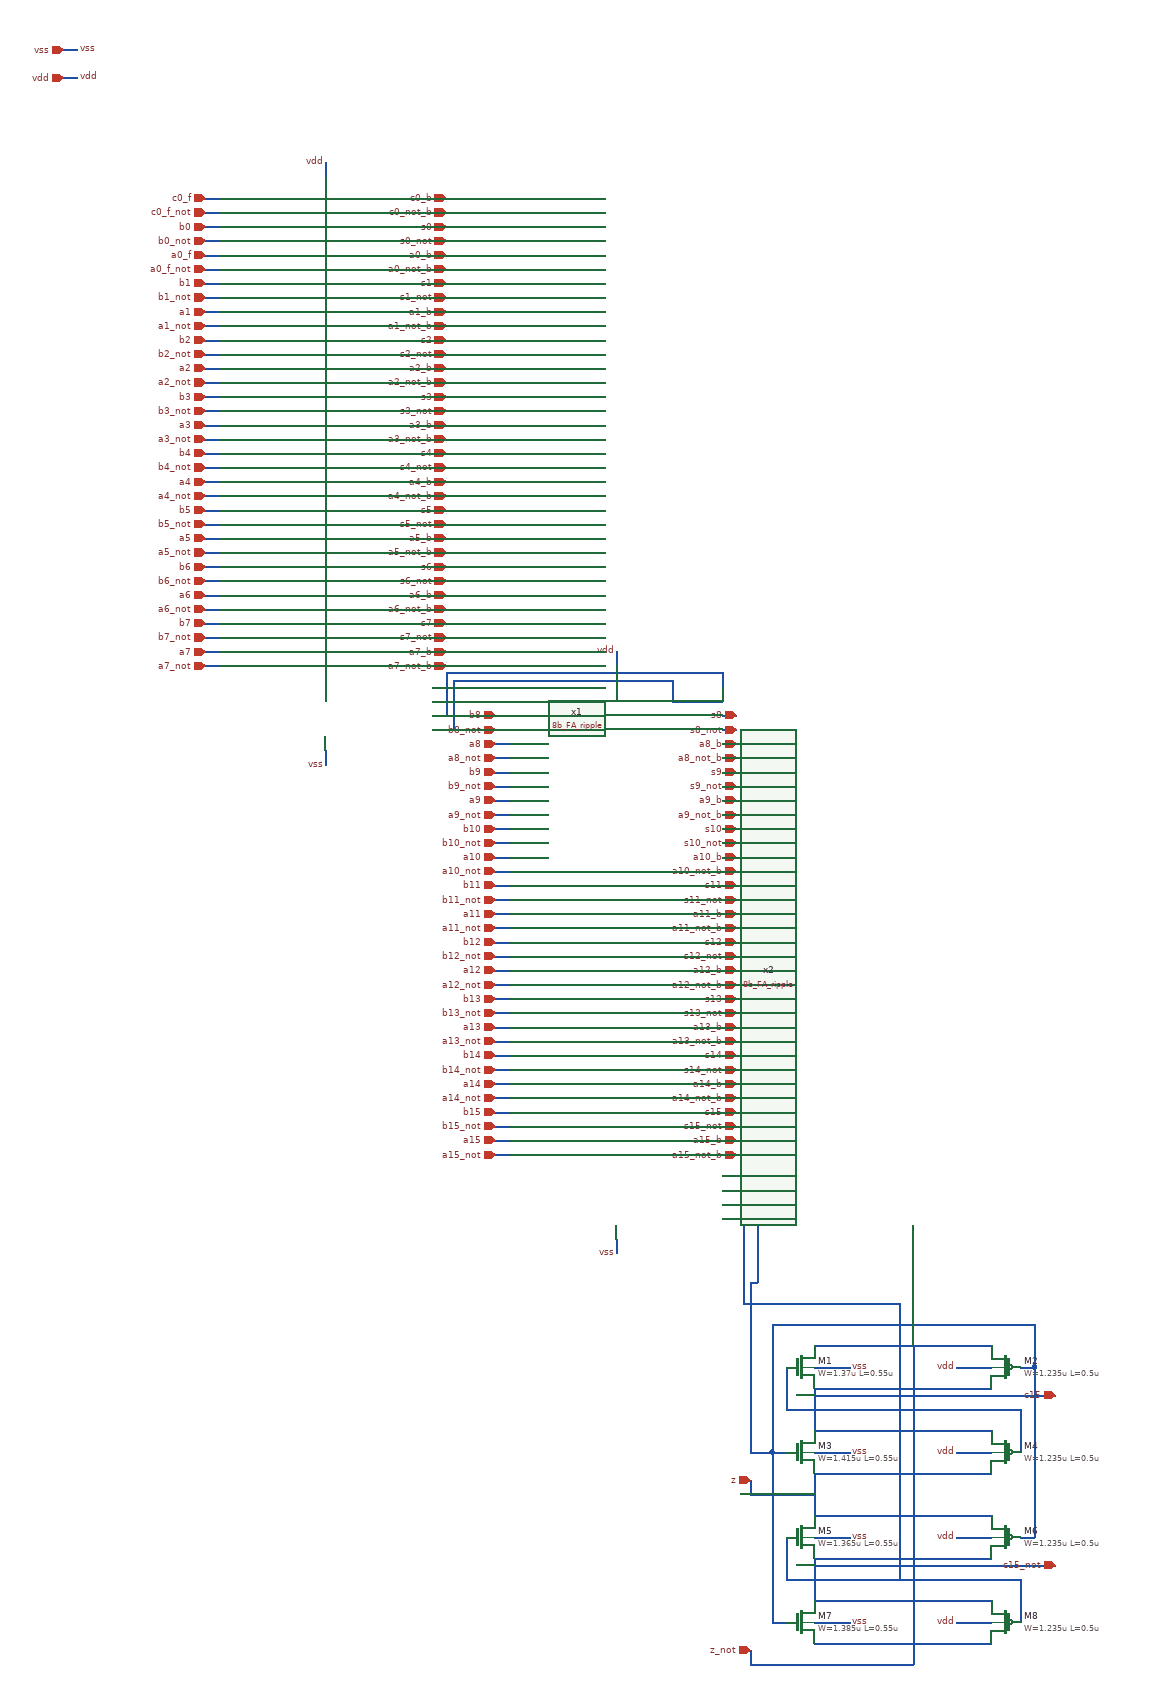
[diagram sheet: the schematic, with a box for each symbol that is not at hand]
v {xschem version=3.4.7 file_version=1.2}
G {}
K {}
V {}
S {}
E {}
N 230 40 340 40 {lab=#net1}
N 230 60 340 60 {lab=#net2}
N 640 770 670 770 {lab=#net3}
N 670 730 670 770 {lab=#net3}
N 640 730 670 730 {lab=#net3}
N 640 750 690 750 {lab=#net4}
N 640 790 690 790 {lab=#net4}
N 690 750 690 790 {lab=#net4}
N 670 770 670 880 {lab=#net3}
N 690 790 690 880 {lab=#net4}
N 230 80 250 80 {lab=#net5}
N 250 30 250 80 {lab=#net5}
N 250 20 250 30 {lab=#net5}
N 250 20 640 20 {lab=#net5}
N 640 20 640 40 {lab=#net5}
N 230 100 260 100 {lab=#net6}
N 260 30 260 100 {lab=#net6}
N 260 30 570 30 {lab=#net6}
N 570 30 570 60 {lab=#net6}
N 570 60 640 60 {lab=#net6}
N 770 970 1020 970 {lab=vss}
N 770 1030 1020 1030 {lab=c15}
N 770 1000 790 1000 {lab=vss}
N 790 1000 820 1000 {lab=vss}
N 970 1000 990 1000 {lab=vdd}
N 990 1000 1020 1000 {lab=vdd}
N 770 1090 1020 1090 {lab=c15}
N 770 1150 1020 1150 {lab=vss}
N 770 1120 790 1120 {lab=vss}
N 790 1120 820 1120 {lab=vss}
N 970 1120 990 1120 {lab=vdd}
N 990 1120 1020 1120 {lab=vdd}
N 770 1030 770 1090 {lab=c15}
N 730 1000 730 1060 {lab=#net3}
N 730 1060 1060 1060 {lab=#net3}
N 1060 1060 1060 1120 {lab=#net3}
N 770 1210 1020 1210 {lab=vss}
N 770 1270 1020 1270 {lab=c15_not}
N 770 1240 790 1240 {lab=vss}
N 790 1240 820 1240 {lab=vss}
N 970 1240 990 1240 {lab=vdd}
N 990 1240 1020 1240 {lab=vdd}
N 770 1330 1020 1330 {lab=c15_not}
N 770 1390 1020 1390 {lab=vss}
N 770 1360 790 1360 {lab=vss}
N 790 1360 820 1360 {lab=vss}
N 970 1360 990 1360 {lab=vdd}
N 990 1360 1020 1360 {lab=vdd}
N 770 1270 770 1330 {lab=c15_not}
N 730 1240 730 1300 {lab=#net3}
N 730 1300 1060 1300 {lab=#net3}
N 1060 1300 1060 1360 {lab=#net3}
N 770 1150 770 1210 {lab=vss}
N 710 1120 730 1120 {lab=#net4}
N 710 910 730 910 {lab=#net3}
N 680 1420 700 1420 {lab=vss}
N 890 910 890 1060 {lab=#net3}
N 890 1060 890 1300 {lab=#net3}
N 680 1120 710 1120 {lab=#net4}
N 1060 1000 1080 1000 {lab=#net4}
N 1080 940 1080 1000 {lab=#net4}
N 1060 1240 1080 1240 {lab=#net4}
N 1080 1000 1080 1240 {lab=#net4}
N 770 1040 1100 1040 {lab=c15}
N 680 1180 770 1180 {lab=vss}
N 670 910 710 910 {lab=#net3}
N 710 1360 730 1360 {lab=#net4}
N 710 940 720 940 {lab=#net4}
N 710 940 710 1120 {lab=#net4}
N 710 1120 710 1360 {lab=#net4}
N 910 970 910 1390 {lab=vss}
N 700 1420 910 1420 {lab=vss}
N 910 1390 910 1420 {lab=vss}
N 1100 1040 1110 1040 {lab=c15}
N 770 1280 1080 1280 {lab=c15_not}
N 1080 1280 1110 1280 {lab=c15_not}
N -290 -860 -270 -860 {lab=vss}
N -290 -820 -270 -820 {lab=vdd}
N 730 910 890 910 {lab=#net3}
N 720 940 1080 940 {lab=#net4}
N 670 880 670 910 {lab=#net3}
N 680 880 680 1120 {lab=#net4}
N 680 880 690 880 {lab=#net4}
N -90 -650 -70 -650 {lab=c0_f}
N -90 -630 -70 -630 {lab=c0_f_not}
N -90 -610 -70 -610 {lab=b0}
N -90 -590 -70 -590 {lab=b0_not}
N -90 -570 -70 -570 {lab=a0_f}
N -90 -550 -70 -550 {lab=a0_f_not}
N -90 -530 -70 -530 {lab=b1}
N -90 -510 -70 -510 {lab=b1_not}
N -90 -490 -70 -490 {lab=a1}
N -90 -470 -70 -470 {lab=a1_not}
N -90 -450 -70 -450 {lab=b2}
N -90 -430 -70 -430 {lab=b2_not}
N -90 -410 -70 -410 {lab=a2}
N -90 -390 -70 -390 {lab=a2_not}
N -90 -370 -70 -370 {lab=b3}
N -90 -350 -70 -350 {lab=b3_not}
N -90 -330 -70 -330 {lab=a3}
N -90 -310 -70 -310 {lab=a3_not}
N -90 -290 -70 -290 {lab=b4}
N -90 -270 -70 -270 {lab=b4_not}
N -90 -250 -70 -250 {lab=a4}
N -90 -230 -70 -230 {lab=a4_not}
N -90 -210 -70 -210 {lab=b5}
N -90 -190 -70 -190 {lab=b5_not}
N -90 -170 -70 -170 {lab=a5}
N -90 -150 -70 -150 {lab=a5_not}
N -90 -130 -70 -130 {lab=b6}
N -90 -110 -70 -110 {lab=b6_not}
N -90 -90 -70 -90 {lab=a6}
N -90 -70 -70 -70 {lab=a6_not}
N -90 -50 -70 -50 {lab=b7}
N -90 -30 -70 -30 {lab=b7_not}
N -90 -10 -70 -10 {lab=a7}
N -90 10 -70 10 {lab=a7_not}
N 230 -650 250 -650 {lab=c0_b}
N 230 -630 250 -630 {lab=c0_not_b}
N 230 -610 250 -610 {lab=s0}
N 230 -590 250 -590 {lab=s0_not}
N 230 -570 250 -570 {lab=a0_b}
N 230 -550 250 -550 {lab=a0_not_b}
N 230 -530 250 -530 {lab=s1}
N 230 -510 250 -510 {lab=s1_not}
N 230 -490 250 -490 {lab=a1_b}
N 230 -470 250 -470 {lab=a1_not_b}
N 230 -450 250 -450 {lab=s2}
N 230 -430 250 -430 {lab=s2_not}
N 230 -410 250 -410 {lab=a2_not}
N 230 -390 250 -390 {lab=a2_not_b}
N 230 -370 250 -370 {lab=s3}
N 230 -350 250 -350 {lab=s3_not}
N 230 -330 250 -330 {lab=a3_b}
N 230 -310 250 -310 {lab=a3_not_b}
N 230 -290 250 -290 {lab=s4}
N 230 -270 250 -270 {lab=s4_not}
N 230 -250 250 -250 {lab=a4_b}
N 230 -230 250 -230 {lab=a4_not_b}
N 230 -210 250 -210 {lab=s5}
N 230 -190 250 -190 {lab=s5_not}
N 230 -170 250 -170 {lab=a5_b}
N 230 -150 250 -150 {lab=a5_not_b}
N 230 -130 250 -130 {lab=s6}
N 230 -110 250 -110 {lab=s6_not}
N 230 -90 250 -90 {lab=a6_b}
N 230 -70 250 -70 {lab=a6_not_b}
N 230 -50 250 -50 {lab=s7}
N 230 -30 250 -30 {lab=s7_not}
N 230 -10 250 -10 {lab=a7_b}
N 230 10 250 10 {lab=a7_not_b}
N 320 80 340 80 {lab=b8}
N 320 100 340 100 {lab=b8_not}
N 320 120 340 120 {lab=a8}
N 320 140 340 140 {lab=a8_not}
N 320 160 340 160 {lab=b9}
N 320 180 340 180 {lab=b9_not}
N 320 200 340 200 {lab=a9}
N 320 220 340 220 {lab=a9_not}
N 320 240 340 240 {lab=b10}
N 320 260 340 260 {lab=b10_not}
N 320 280 340 280 {lab=a10}
N 320 300 340 300 {lab=a10_not}
N 320 320 340 320 {lab=b11}
N 320 340 340 340 {lab=b11_not}
N 320 360 340 360 {lab=a11}
N 320 380 340 380 {lab=a11_not}
N 320 400 340 400 {lab=b12}
N 320 420 340 420 {lab=b12_not}
N 320 440 340 440 {lab=a12}
N 320 460 340 460 {lab=a12_not}
N 320 480 340 480 {lab=b13}
N 320 500 340 500 {lab=b13_not}
N 320 520 340 520 {lab=a13}
N 320 540 340 540 {lab=a13_not}
N 320 560 340 560 {lab=b14}
N 320 580 340 580 {lab=b14_not}
N 320 600 340 600 {lab=a14}
N 320 620 340 620 {lab=a14_not}
N 320 640 340 640 {lab=b15}
N 320 660 340 660 {lab=b15_not}
N 320 680 340 680 {lab=a15}
N 320 700 340 700 {lab=a15_not}
N 640 700 660 700 {lab=a15_not_b}
N 640 680 660 680 {lab=a15_b}
N 640 660 660 660 {lab=s15_not}
N 640 640 660 640 {lab=s15}
N 640 620 660 620 {lab=a14_not_b}
N 640 600 660 600 {lab=a14_b}
N 640 580 660 580 {lab=s14_not}
N 640 560 660 560 {lab=s14}
N 640 540 660 540 {lab=a13_not_b}
N 640 520 660 520 {lab=a13_b}
N 640 500 660 500 {lab=s13_not}
N 640 480 660 480 {lab=s13}
N 640 460 660 460 {lab=a12_not_b}
N 640 440 660 440 {lab=a12_b}
N 640 420 660 420 {lab=s12_not}
N 640 400 660 400 {lab=s12}
N 640 380 660 380 {lab=a11_not_b}
N 640 360 660 360 {lab=a11_b}
N 640 340 660 340 {lab=s11_not}
N 640 320 660 320 {lab=s11}
N 640 300 660 300 {lab=a10_not_b}
N 640 80 660 80 {lab=s8}
N 640 100 660 100 {lab=s8_not}
N 640 120 660 120 {lab=a8_b}
N 640 140 660 140 {lab=a8_not_b}
N 640 160 660 160 {lab=s9}
N 640 180 660 180 {lab=s9_not}
N 640 200 660 200 {lab=a9_b}
N 640 220 660 220 {lab=a9_not_b}
N 640 240 660 240 {lab=s10}
N 640 260 660 260 {lab=s10_not}
N 640 280 660 280 {lab=a10_b}
N 490 820 490 840 {lab=vss}
N 80 130 80 150 {lab=vss}
N 80 -700 80 -680 {lab=vdd}
N 490 -10 490 10 {lab=vdd}
N 680 1160 680 1180 {lab=vss}
N 680 1400 680 1420 {lab=vss}
C {symbols/nfet_03v3.sym} 750 1000 0 0 {name=M1
L=0.55u
W=1.37u
nf=1
m=1
ad="'int((nf+1)/2) * W/nf * 0.18u'"
pd="'2*int((nf+1)/2) * (W/nf + 0.18u)'"
as="'int((nf+2)/2) * W/nf * 0.18u'"
ps="'2*int((nf+2)/2) * (W/nf + 0.18u)'"
nrd="'0.18u / W'" nrs="'0.18u / W'"
sa=0 sb=0 sd=0
model=nfet_03v3
spiceprefix=X
}
C {symbols/pfet_03v3.sym} 1040 1000 2 0 {name=M2
L=0.5u
W=1.235u
nf=1
m=1
ad="'int((nf+1)/2) * W/nf * 0.18u'"
pd="'2*int((nf+1)/2) * (W/nf + 0.18u)'"
as="'int((nf+2)/2) * W/nf * 0.18u'"
ps="'2*int((nf+2)/2) * (W/nf + 0.18u)'"
nrd="'0.18u / W'" nrs="'0.18u / W'"
sa=0 sb=0 sd=0
model=pfet_03v3
spiceprefix=X
}
C {lab_wire.sym} 820 1000 2 0 {name=p2 sig_type=std_logic lab=vss}
C {lab_wire.sym} 970 1000 0 0 {name=p3 sig_type=std_logic lab=vdd}
C {symbols/nfet_03v3.sym} 750 1120 0 0 {name=M3
L=0.55u
W=1.415u
nf=1
m=1
ad="'int((nf+1)/2) * W/nf * 0.18u'"
pd="'2*int((nf+1)/2) * (W/nf + 0.18u)'"
as="'int((nf+2)/2) * W/nf * 0.18u'"
ps="'2*int((nf+2)/2) * (W/nf + 0.18u)'"
nrd="'0.18u / W'" nrs="'0.18u / W'"
sa=0 sb=0 sd=0
model=nfet_03v3
spiceprefix=X
}
C {symbols/pfet_03v3.sym} 1040 1120 2 0 {name=M4
L=0.5u
W=1.235u
nf=1
m=1
ad="'int((nf+1)/2) * W/nf * 0.18u'"
pd="'2*int((nf+1)/2) * (W/nf + 0.18u)'"
as="'int((nf+2)/2) * W/nf * 0.18u'"
ps="'2*int((nf+2)/2) * (W/nf + 0.18u)'"
nrd="'0.18u / W'" nrs="'0.18u / W'"
sa=0 sb=0 sd=0
model=pfet_03v3
spiceprefix=X
}
C {lab_wire.sym} 820 1120 2 0 {name=p4 sig_type=std_logic lab=vss}
C {lab_wire.sym} 970 1120 0 0 {name=p5 sig_type=std_logic lab=vdd}
C {symbols/nfet_03v3.sym} 750 1240 0 0 {name=M5
L=0.55u
W=1.365u
nf=1
m=1
ad="'int((nf+1)/2) * W/nf * 0.18u'"
pd="'2*int((nf+1)/2) * (W/nf + 0.18u)'"
as="'int((nf+2)/2) * W/nf * 0.18u'"
ps="'2*int((nf+2)/2) * (W/nf + 0.18u)'"
nrd="'0.18u / W'" nrs="'0.18u / W'"
sa=0 sb=0 sd=0
model=nfet_03v3
spiceprefix=X
}
C {symbols/pfet_03v3.sym} 1040 1240 2 0 {name=M6
L=0.5u
W=1.235u
nf=1
m=1
ad="'int((nf+1)/2) * W/nf * 0.18u'"
pd="'2*int((nf+1)/2) * (W/nf + 0.18u)'"
as="'int((nf+2)/2) * W/nf * 0.18u'"
ps="'2*int((nf+2)/2) * (W/nf + 0.18u)'"
nrd="'0.18u / W'" nrs="'0.18u / W'"
sa=0 sb=0 sd=0
model=pfet_03v3
spiceprefix=X
}
C {lab_wire.sym} 820 1240 2 0 {name=p6 sig_type=std_logic lab=vss}
C {lab_wire.sym} 970 1240 0 0 {name=p7 sig_type=std_logic lab=vdd}
C {symbols/nfet_03v3.sym} 750 1360 0 0 {name=M7
L=0.55u
W=1.385u
nf=1
m=1
ad="'int((nf+1)/2) * W/nf * 0.18u'"
pd="'2*int((nf+1)/2) * (W/nf + 0.18u)'"
as="'int((nf+2)/2) * W/nf * 0.18u'"
ps="'2*int((nf+2)/2) * (W/nf + 0.18u)'"
nrd="'0.18u / W'" nrs="'0.18u / W'"
sa=0 sb=0 sd=0
model=nfet_03v3
spiceprefix=X
}
C {symbols/pfet_03v3.sym} 1040 1360 2 0 {name=M8
L=0.5u
W=1.235u
nf=1
m=1
ad="'int((nf+1)/2) * W/nf * 0.18u'"
pd="'2*int((nf+1)/2) * (W/nf + 0.18u)'"
as="'int((nf+2)/2) * W/nf * 0.18u'"
ps="'2*int((nf+2)/2) * (W/nf + 0.18u)'"
nrd="'0.18u / W'" nrs="'0.18u / W'"
sa=0 sb=0 sd=0
model=pfet_03v3
spiceprefix=X
}
C {lab_wire.sym} 820 1360 2 0 {name=p8 sig_type=std_logic lab=vss}
C {lab_wire.sym} 970 1360 0 0 {name=p9 sig_type=std_logic lab=vdd}
C {iopin.sym} -290 -860 2 0 {name=p13 lab=vss}
C {iopin.sym} -290 -820 2 0 {name=p14 lab=vdd}
C {iopin.sym} 1110 1040 0 0 {name=p15 lab=c15}
C {iopin.sym} 1110 1280 0 0 {name=p18 lab=c15_not}
C {lab_wire.sym} -270 -860 2 0 {name=p19 sig_type=std_logic lab=vss}
C {lab_wire.sym} -270 -820 2 0 {name=p20 sig_type=std_logic lab=vdd}
C {iopin.sym} -90 -630 2 0 {name=p11 lab=c0_f_not}
C {iopin.sym} -90 -570 2 0 {name=p12 lab=a0_f}
C {iopin.sym} -90 -650 2 0 {name=p16 lab=c0_f}
C {iopin.sym} -90 -610 2 0 {name=p17 lab=b0}
C {iopin.sym} -90 -550 2 0 {name=p21 lab=a0_f_not}
C {iopin.sym} -90 -510 2 0 {name=p22 lab=b1_not}
C {iopin.sym} -90 -590 2 0 {name=p23 lab=b0_not}
C {iopin.sym} -90 -530 2 0 {name=p24 lab=b1}
C {iopin.sym} -90 -470 2 0 {name=p25 lab=a1_not}
C {iopin.sym} -90 -430 2 0 {name=p26 lab=b2_not}
C {iopin.sym} -90 -490 2 0 {name=p27 lab=a1}
C {iopin.sym} -90 -450 2 0 {name=p28 lab=b2}
C {iopin.sym} -90 -390 2 0 {name=p29 lab=a2_not}
C {iopin.sym} -90 -350 2 0 {name=p30 lab=b3_not}
C {iopin.sym} -90 -410 2 0 {name=p31 lab=a2}
C {iopin.sym} -90 -370 2 0 {name=p32 lab=b3}
C {iopin.sym} -90 -310 2 0 {name=p33 lab=a3_not}
C {iopin.sym} -90 -270 2 0 {name=p34 lab=b4_not}
C {iopin.sym} -90 -330 2 0 {name=p35 lab=a3}
C {iopin.sym} -90 -290 2 0 {name=p36 lab=b4}
C {iopin.sym} -90 -230 2 0 {name=p37 lab=a4_not}
C {iopin.sym} -90 -190 2 0 {name=p38 lab=b5_not}
C {iopin.sym} -90 -250 2 0 {name=p39 lab=a4}
C {iopin.sym} -90 -210 2 0 {name=p40 lab=b5}
C {iopin.sym} -90 -150 2 0 {name=p41 lab=a5_not}
C {iopin.sym} -90 -110 2 0 {name=p42 lab=b6_not}
C {iopin.sym} -90 -170 2 0 {name=p43 lab=a5}
C {iopin.sym} -90 -130 2 0 {name=p44 lab=b6}
C {iopin.sym} -90 -70 2 0 {name=p45 lab=a6_not}
C {iopin.sym} -90 -30 2 0 {name=p46 lab=b7_not}
C {iopin.sym} -90 -90 2 0 {name=p47 lab=a6}
C {iopin.sym} -90 -50 2 0 {name=p48 lab=b7}
C {iopin.sym} -90 10 2 0 {name=p49 lab=a7_not}
C {iopin.sym} -90 -10 2 0 {name=p50 lab=a7}
C {iopin.sym} 250 -10 0 0 {name=p51 lab=a7_b}
C {iopin.sym} 250 -50 0 0 {name=p52 lab=s7}
C {iopin.sym} 250 10 0 0 {name=p53 lab=a7_not_b}
C {iopin.sym} 250 -30 0 0 {name=p54 lab=s7_not}
C {iopin.sym} 250 -90 0 0 {name=p55 lab=a6_b}
C {iopin.sym} 250 -130 0 0 {name=p56 lab=s6}
C {iopin.sym} 250 -70 0 0 {name=p57 lab=a6_not_b}
C {iopin.sym} 250 -110 0 0 {name=p58 lab=s6_not}
C {iopin.sym} 250 -170 0 0 {name=p59 lab=a5_b}
C {iopin.sym} 250 -210 0 0 {name=p60 lab=s5}
C {iopin.sym} 250 -150 0 0 {name=p61 lab=a5_not_b}
C {iopin.sym} 250 -190 0 0 {name=p62 lab=s5_not}
C {iopin.sym} 250 -250 0 0 {name=p63 lab=a4_b}
C {iopin.sym} 250 -290 0 0 {name=p64 lab=s4}
C {iopin.sym} 250 -230 0 0 {name=p65 lab=a4_not_b}
C {iopin.sym} 250 -270 0 0 {name=p66 lab=s4_not}
C {iopin.sym} 250 -330 0 0 {name=p67 lab=a3_b}
C {iopin.sym} 250 -370 0 0 {name=p68 lab=s3}
C {iopin.sym} 250 -310 0 0 {name=p69 lab=a3_not_b}
C {iopin.sym} 250 -350 0 0 {name=p70 lab=s3_not}
C {iopin.sym} 250 -410 0 0 {name=p71 lab=a2_b}
C {iopin.sym} 250 -450 0 0 {name=p72 lab=s2}
C {iopin.sym} 250 -390 0 0 {name=p73 lab=a2_not_b}
C {iopin.sym} 250 -430 0 0 {name=p74 lab=s2_not}
C {iopin.sym} 250 -490 0 0 {name=p75 lab=a1_b}
C {iopin.sym} 250 -530 0 0 {name=p76 lab=s1}
C {iopin.sym} 250 -470 0 0 {name=p77 lab=a1_not_b}
C {iopin.sym} 250 -510 0 0 {name=p78 lab=s1_not}
C {iopin.sym} 250 -570 0 0 {name=p79 lab=a0_b}
C {iopin.sym} 250 -610 0 0 {name=p80 lab=s0}
C {iopin.sym} 250 -550 0 0 {name=p81 lab=a0_not_b}
C {iopin.sym} 250 -590 0 0 {name=p82 lab=s0_not}
C {iopin.sym} 250 -650 0 0 {name=p83 lab=c0_b}
C {iopin.sym} 250 -630 0 0 {name=p84 lab=c0_not_b}
C {iopin.sym} 320 100 2 0 {name=p85 lab=b8_not}
C {iopin.sym} 320 140 2 0 {name=p86 lab=a8_not}
C {iopin.sym} 320 80 2 0 {name=p87 lab=b8}
C {iopin.sym} 320 120 2 0 {name=p88 lab=a8}
C {iopin.sym} 320 180 2 0 {name=p89 lab=b9_not}
C {iopin.sym} 320 220 2 0 {name=p90 lab=a9_not}
C {iopin.sym} 320 160 2 0 {name=p91 lab=b9}
C {iopin.sym} 320 200 2 0 {name=p92 lab=a9}
C {iopin.sym} 320 260 2 0 {name=p93 lab=b10_not}
C {iopin.sym} 320 300 2 0 {name=p94 lab=a10_not}
C {iopin.sym} 320 240 2 0 {name=p95 lab=b10}
C {iopin.sym} 320 280 2 0 {name=p96 lab=a10}
C {iopin.sym} 320 340 2 0 {name=p97 lab=b11_not}
C {iopin.sym} 320 380 2 0 {name=p98 lab=a11_not}
C {iopin.sym} 320 320 2 0 {name=p99 lab=b11}
C {iopin.sym} 320 360 2 0 {name=p100 lab=a11}
C {iopin.sym} 320 420 2 0 {name=p101 lab=b12_not}
C {iopin.sym} 320 460 2 0 {name=p102 lab=a12_not}
C {iopin.sym} 320 400 2 0 {name=p103 lab=b12}
C {iopin.sym} 320 440 2 0 {name=p104 lab=a12}
C {iopin.sym} 320 500 2 0 {name=p105 lab=b13_not}
C {iopin.sym} 320 540 2 0 {name=p106 lab=a13_not}
C {iopin.sym} 320 480 2 0 {name=p107 lab=b13}
C {iopin.sym} 320 520 2 0 {name=p108 lab=a13}
C {iopin.sym} 320 580 2 0 {name=p109 lab=b14_not}
C {iopin.sym} 320 620 2 0 {name=p110 lab=a14_not}
C {iopin.sym} 320 560 2 0 {name=p111 lab=b14}
C {iopin.sym} 320 600 2 0 {name=p112 lab=a14}
C {iopin.sym} 320 660 2 0 {name=p113 lab=b15_not}
C {iopin.sym} 320 700 2 0 {name=p114 lab=a15_not}
C {iopin.sym} 320 640 2 0 {name=p115 lab=b15}
C {iopin.sym} 320 680 2 0 {name=p116 lab=a15}
C {iopin.sym} 660 680 0 0 {name=p117 lab=a15_b}
C {iopin.sym} 660 640 0 0 {name=p118 lab=s15}
C {iopin.sym} 660 660 0 0 {name=p119 lab=s15_not}
C {iopin.sym} 660 600 0 0 {name=p120 lab=a14_b}
C {iopin.sym} 660 560 0 0 {name=p121 lab=s14}
C {iopin.sym} 660 620 0 0 {name=p122 lab=a14_not_b}
C {iopin.sym} 660 580 0 0 {name=p123 lab=s14_not}
C {iopin.sym} 660 520 0 0 {name=p124 lab=a13_b}
C {iopin.sym} 660 480 0 0 {name=p125 lab=s13}
C {iopin.sym} 660 540 0 0 {name=p126 lab=a13_not_b}
C {iopin.sym} 660 500 0 0 {name=p127 lab=s13_not}
C {iopin.sym} 660 440 0 0 {name=p128 lab=a12_b}
C {iopin.sym} 660 400 0 0 {name=p129 lab=s12}
C {iopin.sym} 660 460 0 0 {name=p130 lab=a12_not_b}
C {iopin.sym} 660 420 0 0 {name=p131 lab=s12_not}
C {iopin.sym} 660 360 0 0 {name=p132 lab=a11_b}
C {iopin.sym} 660 320 0 0 {name=p133 lab=s11}
C {iopin.sym} 660 380 0 0 {name=p134 lab=a11_not_b}
C {iopin.sym} 660 340 0 0 {name=p135 lab=s11_not}
C {iopin.sym} 660 280 0 0 {name=p136 lab=a10_b}
C {iopin.sym} 660 240 0 0 {name=p137 lab=s10}
C {iopin.sym} 660 300 0 0 {name=p138 lab=a10_not_b}
C {iopin.sym} 660 260 0 0 {name=p139 lab=s10_not}
C {iopin.sym} 660 200 0 0 {name=p140 lab=a9_b}
C {iopin.sym} 660 160 0 0 {name=p141 lab=s9}
C {iopin.sym} 660 220 0 0 {name=p142 lab=a9_not_b}
C {iopin.sym} 660 180 0 0 {name=p143 lab=s9_not}
C {iopin.sym} 660 120 0 0 {name=p144 lab=a8_b}
C {iopin.sym} 660 80 0 0 {name=p145 lab=s8}
C {iopin.sym} 660 140 0 0 {name=p146 lab=a8_not_b}
C {iopin.sym} 660 100 0 0 {name=p147 lab=s8_not}
C {iopin.sym} 660 700 0 0 {name=p150 lab=a15_not_b}
C {lab_wire.sym} 490 840 0 0 {name=p148 sig_type=std_logic lab=vss}
C {lab_wire.sym} 80 150 0 0 {name=p149 sig_type=std_logic lab=vss}
C {lab_wire.sym} 80 -700 0 0 {name=p151 sig_type=std_logic lab=vdd}
C {lab_wire.sym} 490 -10 0 0 {name=p152 sig_type=std_logic lab=vdd}
C {final_project/devices/8b_FA_ripple/8b_FA_ripple.sym} 80 -20 0 0 {name=x1}
C {final_project/devices/8b_FA_ripple/8b_FA_ripple.sym} 490 670 0 0 {name=x2}
C {iopin.sym} 680 1400 2 0 {name=p10 lab=z_not}
C {iopin.sym} 680 1160 2 0 {name=p154 lab=z}
